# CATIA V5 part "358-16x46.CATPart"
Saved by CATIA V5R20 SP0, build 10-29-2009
Part number: 358-16X46
Definition: NONE
Nomenclature: 358-16X46
Source: Unknown
Description: 358-16X46
Bounding box of the stored display mesh (mm): x -15 to 31, y -13 to 13, z -13 to 13
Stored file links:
  C:\Users\Utente\Desktop\IO LAVORO\3D X SITO CF\X SITO\PLASTICA\358\358-16x46.CATPart

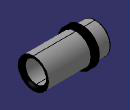
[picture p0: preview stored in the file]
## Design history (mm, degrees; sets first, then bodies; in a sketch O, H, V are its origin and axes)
Body1 "358-16X46" (main body)
  Solid1: solid without history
